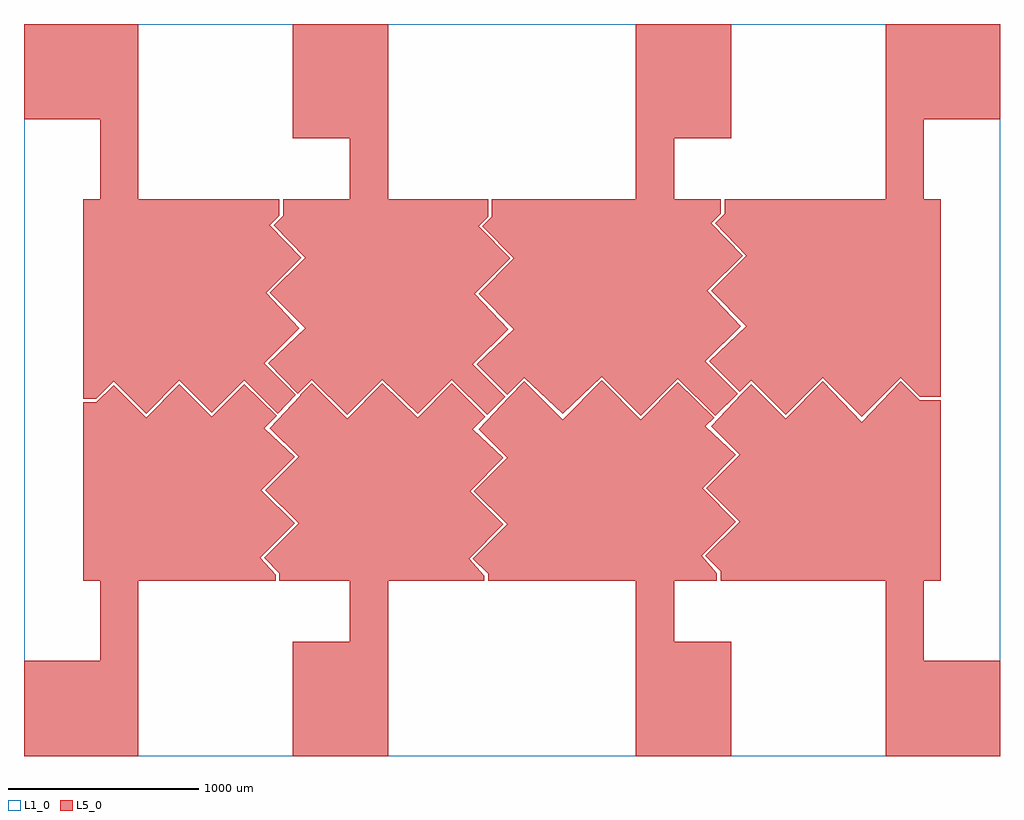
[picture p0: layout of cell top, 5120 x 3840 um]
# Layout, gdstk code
import gdstk
lib = gdstk.Library(unit=1e-6, precision=5e-06)
def R(c, l, rs):  # rectangles x0, y0, x1, y1
    for r in rs: c.add(gdstk.rectangle(r[:2], r[2:], *l))
def P(c, l, *ps):  # polygons
    for p in ps: c.add(gdstk.Polygon(p, *l))
L1_0 = (1, 0)
L5_0 = (5, 0)

opendropelectrode = lib.new_cell('OpenDropElectrode')

top = lib.new_cell('top')
R(top, L1_0, [(0,0,5120,3840)])
P(top, L1_0, [(0,0),(0,0),(0,0),(0,0)])
P(top, L5_0, [(0,0),(0,500),(400,500),(400,920),(310,920),(310,1855),(380,1855),(470,1945),(640,1775),(815,1950),(985,1780),(1155,1950),(1325,1785),(1260,1720),(1420,1570),(1245,1395),(1420,1220),(1240,1040),(1320,950),(1320,920),(600,920),(600,0)],
  [(640,1795),(470,1965),(380,1875),(310,1875),(310,2920),(400,2920),(400,3340),(0,3340),(0,3840),(600,3840),(600,2920),(1340,2920),(1340,2835),(1290,2785),(1455,2615),(1270,2430),(1445,2245),(1260,2060),(1425,1895),(1330,1795),(1155,1970),(985,1800),(815,1970)],
  [(1695,1790),(1510,1975),(1435,1900),(1280,2060),(1475,2245),(1290,2430),(1475,2615),(1310,2785),(1360,2835),(1360,2920),(1710,2920),(1710,3240),(1410,3240),(1410,3840),(1910,3840),(1910,2920),(2435,2920),(2435,2830),(2385,2780),(2550,2610),(2365,2425),(2540,2240),(2355,2055),(2525,1885),(2430,1790),(2245,1975),(2065,1795),(1880,1975)],
  [(1410,0),(1410,600),(1710,600),(1710,920),(1340,920),(1340,960),(1260,1040),(1440,1220),(1265,1395),(1440,1570),(1290,1720),(1450,1890),(1450,1895),(1510,1955),(1695,1770),(1880,1955),(2065,1775),(2245,1955),(2420,1780),(2355,1715),(2515,1565),(2340,1390),(2515,1215),(2335,1035),(2415,945),(2415,920),(1910,920),(1910,0)],
  [(3235,1785),(3030,1990),(2825,1795),(2625,1985),(2535,1895),(2375,2055),(2570,2240),(2385,2425),(2570,2610),(2405,2780),(2455,2830),(2455,2920),(3210,2920),(3210,3840),(3710,3840),(3710,3240),(3410,3240),(3410,2920),(3655,2920),(3655,2845),(3605,2795),(3770,2625),(3585,2440),(3760,2255),(3575,2070),(3745,1900),(3625,1785),(3430,1980)],
  [(4520,0),(4520,920),(3655,920),(3655,970),(3575,1050),(3755,1230),(3580,1405),(3755,1580),(3605,1730),(3765,1900),(3815,1950),(3995,1770),(4190,1965),(4395,1750),(4600,1965),(4700,1865),(4810,1865),(4810,920),(4720,920),(4720,500),(5120,500),(5120,0)],
  [(4395,1780),(4190,1985),(3995,1790),(3815,1970),(3755,1910),(3595,2070),(3790,2255),(3605,2440),(3790,2625),(3625,2795),(3675,2845),(3675,2920),(4520,2920),(4520,3840),(5120,3840),(5120,3340),(4720,3340),(4720,2920),(4810,2920),(4810,1885),(4700,1885),(4600,1985)],
  [(3210,0),(3210,920),(2435,920),(2435,955),(2355,1035),(2535,1215),(2360,1390),(2535,1565),(2385,1715),(2545,1885),(2625,1965),(2825,1765),(3030,1970),(3235,1765),(3430,1960),(3620,1775),(3575,1730),(3735,1580),(3560,1405),(3735,1230),(3555,1050),(3635,960),(3635,920),(3410,920),(3410,600),(3710,600),(3710,0)])
r = gdstk.Reference(opendropelectrode, (765,1325)); r.repetition = gdstk.Repetition(4, 2, v1=(1200,0), v2=(0,1200)); top.add(r)

lib.write_gds('top.gds')
